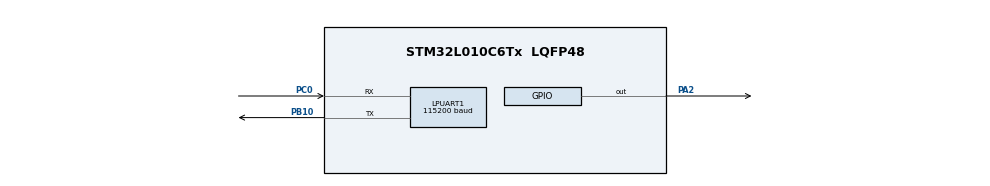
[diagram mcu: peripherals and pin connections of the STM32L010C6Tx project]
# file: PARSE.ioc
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LPUART1.BaudRate=115200
LPUART1.WordLength=UART_WORDLENGTH_8B
Mcu.Family=STM32L0
Mcu.Name=STM32L010C6Tx
Mcu.Package=LQFP48
NVIC.LPUART1_IRQn=true\:0\:0\:false\:false\:true\:true\:true
PA13.Mode=Serial_Wire
PA13.Signal=SYS_SWDIO
PA14.Mode=Serial_Wire
PA14.Signal=SYS_SWCLK
PA2.Signal=GPIO_Output
PB10.Mode=Multiprocessor_communication
PB10.Signal=LPUART1_TX
PC0.Mode=Multiprocessor_communication
PC0.Signal=LPUART1_RX
ProjectManager.HeapSize=0x200
ProjectManager.StackSize=0x400
ProjectManager.TargetToolchain=STM32CubeIDE
RCC.AHBFreq_Value=2097000
RCC.APB1Freq_Value=2097000
RCC.APB1TimFreq_Value=2097000
RCC.APB2Freq_Value=2097000
RCC.APB2TimFreq_Value=2097000
RCC.HSE_VALUE=8000000
RCC.HSI16_VALUE=16000000
RCC.HSI_VALUE=16000000
RCC.LSE_VALUE=32768
RCC.MSI_VALUE=2097000
RCC.SYSCLKFreq_VALUE=2097000
RCC.VCOOutputFreq_Value=48000000
board=custom

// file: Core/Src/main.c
/* USER CODE BEGIN Header */
/**
  ******************************************************************************
  * @file           : main.c
  * @brief          : Main program body
  ******************************************************************************
  * @attention
  *
  * Copyright (c) 2022 STMicroelectronics.
  * All rights reserved.
  *
  * This software is licensed under terms that can be found in the LICENSE file
  * in the root directory of this software component.
  * If no LICENSE file comes with this software, it is provided AS-IS.
  *
  ******************************************************************************
  */
/* USER CODE END Header */
#include "main.h"

UART_HandleTypeDef hlpuart1;

void SystemClock_Config(void);
static void MX_GPIO_Init(void);
static void MX_LPUART1_UART_Init(void);

/* USER CODE BEGIN 0 */
uint8_t Rxdata[5] = {0};
char sayac[5];

void HAL_UART_RxCpltCallback(UART_HandleTypeDef *huart)
{
	  //HAL_UART_Receive_IT(&hlpuart1, Rxdata, 5);
	  //AL_UART_Receive_IT(&hlpuart1, Rxdata, 5);
	  HAL_UART_Transmit_IT(&hlpuart1, Rxdata, 5);
	  HAL_UART_Transmit_IT(&hlpuart1, "\r\n", 2);
	  HAL_UART_Receive_IT(&hlpuart1, Rxdata, 5);

}

/* USER CODE END 0 */

int main(void)
{

  /* MCU Configuration--------------------------------------------------------*/

  /* Reset of all peripherals, Initializes the Flash interface and the Systick. */
  HAL_Init();

  /* Configure the system clock */
  SystemClock_Config();

  /* Initialize all configured peripherals */
  MX_GPIO_Init();
  MX_LPUART1_UART_Init();
  /* USER CODE BEGIN 2 */
  HAL_UART_Receive_IT(&hlpuart1, Rxdata, 5);
  /* USER CODE END 2 */

  /* Infinite loop */
  while (1)
  {

    /* USER CODE BEGIN 3 */
// 	  HAL_UART_Receive_IT (&hlpuart1, Rxdata, 5);
	    int x = atoi(Rxdata);
		if (x == 9000){

		HAL_UART_Transmit_IT(&hlpuart1, "test", 5);
		}
	  HAL_Delay(300);

  }
  /* USER CODE END 3 */
}

void SystemClock_Config(void)
{
  RCC_OscInitTypeDef RCC_OscInitStruct = {0};
  RCC_ClkInitTypeDef RCC_ClkInitStruct = {0};
  RCC_PeriphCLKInitTypeDef PeriphClkInit = {0};

  /** Configure the main internal regulator output voltage
  */
  __HAL_PWR_VOLTAGESCALING_CONFIG(PWR_REGULATOR_VOLTAGE_SCALE1);
  /** Initializes the RCC Oscillators according to the specified parameters
  * in the RCC_OscInitTypeDef structure.
  */
  RCC_OscInitStruct.OscillatorType = RCC_OSCILLATORTYPE_HSI;
  RCC_OscInitStruct.HSIState = RCC_HSI_ON;
  RCC_OscInitStruct.HSICalibrationValue = RCC_HSICALIBRATION_DEFAULT;
  RCC_OscInitStruct.PLL.PLLState = RCC_PLL_ON;
  RCC_OscInitStruct.PLL.PLLSource = RCC_PLLSOURCE_HSI;
  RCC_OscInitStruct.PLL.PLLMUL = RCC_PLLMUL_4;
  RCC_OscInitStruct.PLL.PLLDIV = RCC_PLLDIV_2;
  if (HAL_RCC_OscConfig(&RCC_OscInitStruct) != HAL_OK)
  {
    Error_Handler();
  }
  /** Initializes the CPU, AHB and APB buses clocks
  */
  RCC_ClkInitStruct.ClockType = RCC_CLOCKTYPE_HCLK|RCC_CLOCKTYPE_SYSCLK
                              |RCC_CLOCKTYPE_PCLK1|RCC_CLOCKTYPE_PCLK2;
  RCC_ClkInitStruct.SYSCLKSource = RCC_SYSCLKSOURCE_PLLCLK;
  RCC_ClkInitStruct.AHBCLKDivider = RCC_SYSCLK_DIV1;
  RCC_ClkInitStruct.APB1CLKDivider = RCC_HCLK_DIV1;
  RCC_ClkInitStruct.APB2CLKDivider = RCC_HCLK_DIV1;

  if (HAL_RCC_ClockConfig(&RCC_ClkInitStruct, FLASH_LATENCY_1) != HAL_OK)
  {
    Error_Handler();
  }
  PeriphClkInit.PeriphClockSelection = RCC_PERIPHCLK_LPUART1;
  PeriphClkInit.Lpuart1ClockSelection = RCC_LPUART1CLKSOURCE_PCLK1;
  if (HAL_RCCEx_PeriphCLKConfig(&PeriphClkInit) != HAL_OK)
  {
    Error_Handler();
  }
}

static void MX_LPUART1_UART_Init(void)
{

  hlpuart1.Instance = LPUART1;
  hlpuart1.Init.BaudRate = 115200;
  hlpuart1.Init.WordLength = UART_WORDLENGTH_8B;
  hlpuart1.Init.StopBits = UART_STOPBITS_1;
  hlpuart1.Init.Parity = UART_PARITY_NONE;
  hlpuart1.Init.Mode = UART_MODE_TX_RX;
  hlpuart1.Init.HwFlowCtl = UART_HWCONTROL_NONE;
  hlpuart1.Init.OneBitSampling = UART_ONE_BIT_SAMPLE_DISABLE;
  hlpuart1.AdvancedInit.AdvFeatureInit = UART_ADVFEATURE_NO_INIT;
  if (HAL_UART_Init(&hlpuart1) != HAL_OK)
  {
    Error_Handler();
  }

}

static void MX_GPIO_Init(void)
{

  /* GPIO Ports Clock Enable */
  __HAL_RCC_GPIOC_CLK_ENABLE();
  __HAL_RCC_GPIOA_CLK_ENABLE();

}

void Error_Handler(void)
{
  __disable_irq();
  while (1)
  {
  }
}
